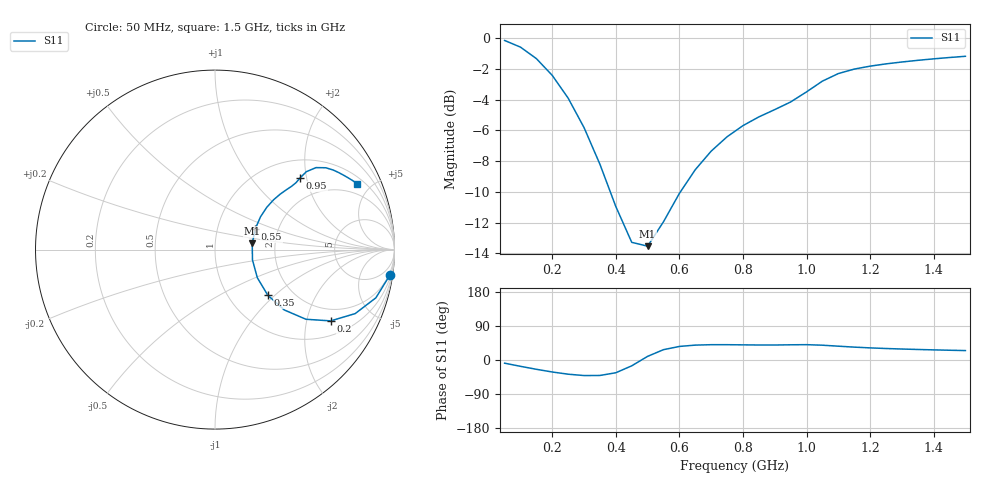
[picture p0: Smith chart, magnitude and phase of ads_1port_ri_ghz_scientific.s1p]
! Created Fri Aug 21 13:39:58 2026
# ghz S ri R 50
! 1 Port Network Data from SP1.SP block
! freq  reS11  imS11
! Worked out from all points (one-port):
!   30 points, 50 MHz to 1.5 GHz, reference 50 ohm
!   lowest |S11| = -13.5 dB at 500 MHz (marker M1), VSWR 1.53, Z = 75.9 + j5.59 ohm
!   |S11| at or under -10 dB: 382.5 MHz to 603.3 MHz (220.8 MHz wide, 44.8 % of centre)
!   S11 on the Smith chart (normalised r, x): 50 MHz: 2, -13; 200 MHz: 1.50, -2.79; 350 MHz: 1.51, -0.90; 550 MHz: 1.52, +0.38; 950 MHz: 1.41, +1.83; 1.5 GHz: 1.33, +4.13
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0.05  0.9731 -0.1443
0.1  0.8962 -0.2687
0.15  0.7809 -0.3566
0.2  0.6444 -0.3972
0.25  0.5067 -0.3881
0.3  0.3859 -0.3361
0.35  0.2941 -0.254
0.4  0.2357 -0.1568
0.45  0.2088 -0.0574
0.5  0.2074 0.0352
0.55  0.2245 0.1158
0.6  0.2535 0.1827
0.65  0.289 0.2363
0.7  0.3268 0.2779
0.75  0.3639 0.3095
0.8  0.398 0.3336
0.85  0.4274 0.3532
0.9  0.4515 0.373
0.95  0.4742 0.3997
1  0.5089 0.434
1.05  0.5631 0.4569
1.1  0.6171 0.456
1.15  0.658 0.4436
1.2  0.6882 0.4296
1.25  0.7122 0.4168
1.35  0.7498 0.3949
1.4  0.7655 0.3853
1.5  0.7925 0.3675
